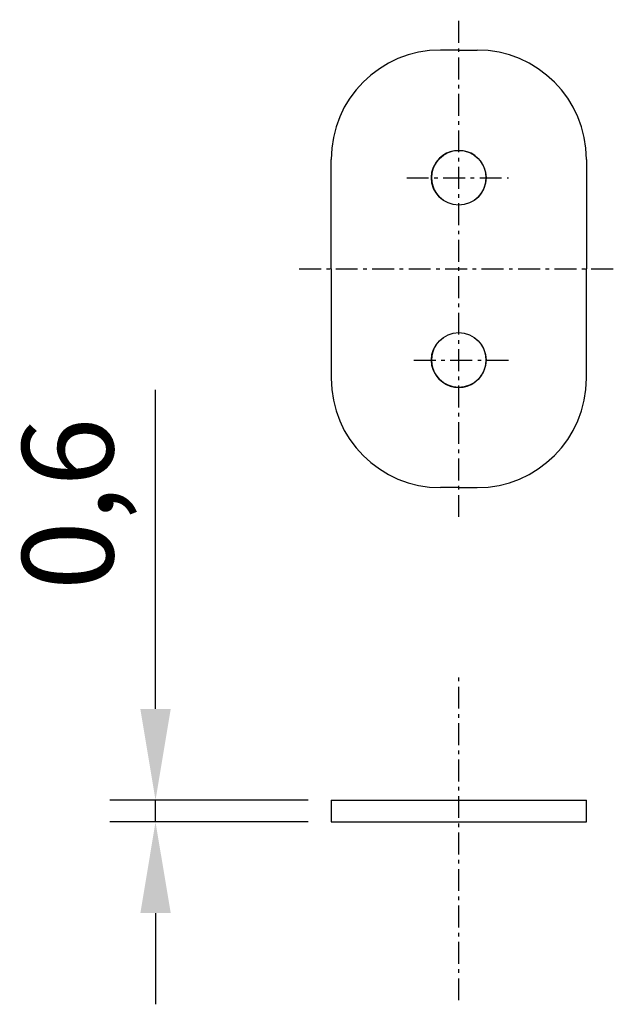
# Model space of a CAD drawing. Units: millimetres. Extents: x -21 to -4.8, y 140.5 to 167.5.
import ezdxf

# ---------------------------------------------------------------- set-up
doc = ezdxf.new("R2010")
doc.units = ezdxf.units.MM
doc.header["$LTSCALE"] = 0.2
doc.linetypes.add('ACAD_ISO10W100', pattern=[18, 12, -3, 0, -3])
doc.dimstyles.new('ISO-25', dxfattribs={"dimtxt": 2.5, "dimasz": 2.5, "dimexe": 1.25, "dimexo": 0.625, "dimtad": 1, "dimtxsty": 'Standard', "dimcen": 2.5, "dimadec": 0, "dimazin": 0, "dimtfac": 1, "dimtmove": 0, "dimatfit": 3, "dimfxl": 0, "dimarcsym": 0})

# ---------------------------------------------------------------- blocks, each defined once
blk = doc.blocks.new('*D1')
at = {"color": 0, "lineweight": -2, "ltscale": 0.25}
for p, q in [((-17.314, 148.583), (-17.314, 157.333)), ((-13.125, 146.083), (-18.564, 146.083)), ((-17.314, 145.483), (-17.314, 146.083)), ((-13.125, 145.483), (-18.564, 145.483)), ((-17.314, 142.983), (-17.314, 140.483))]:
    blk.add_line(p, q, dxfattribs=at)
at = {"color": 0, "lineweight": 15, "ltscale": 0.25}
for points in [[(-17.73, 148.583), (-16.897, 148.583), (-17.314, 146.083)], [(-17.73, 142.983), (-16.897, 142.983), (-17.314, 145.483)]]:
    blk.add_solid(points, dxfattribs=at)
at = {"layer": 'Defpoints', "color": 0, "lineweight": 15, "ltscale": 0.25}
for p in [(-17.314, 146.083), (-12.5, 146.083), (-12.5, 145.483)]:
    blk.add_point(p, dxfattribs=at)
at = {"color": 0, "lineweight": 15, "ltscale": 0.25, "insert": (-19.397, 154.208), "char_height": 2.5, "attachment_point": 5, "rotation": 90}
blk.add_mtext('0,6', dxfattribs=at)

msp = doc.modelspace()

# ---------------------------------------------------------------- linework, layer by layer
at = {"color": 1, "linetype": 'ACAD_ISO10W100', "lineweight": 25, "ltscale": 0.25}
for p, q in [((-9, 153.849), (-9, 167.485)), ((-10.426, 163.152), (-7.634, 163.152)), ((-13.373, 160.652), (-5.137, 160.652)), ((-5.137, 160.652), (-4.764, 160.652)), ((-10.232, 158.152), (-7.634, 158.152)), ((-9, 140.593), (-9, 149.533))]:
    msp.add_line(p, q, dxfattribs=at)
at = {"color": 7, "lineweight": 30, "ltscale": 0.25}
for p, q in [((-9, 166.652), (-9.5, 166.652)), ((-9, 166.652), (-8.5, 166.652)), ((-12.5, 160.652), (-12.5, 163.652)), ((-5.5, 163.652), (-5.5, 160.652)), ((-12.5, 160.652), (-12.5, 157.652)), ((-5.5, 157.652), (-5.5, 160.652)), ((-9, 154.652), (-9.5, 154.652)), ((-9, 154.652), (-8.5, 154.652)), ((-12.5, 146.083), (-12.5, 145.483)), ((-12.5, 146.083), (-5.5, 146.083)), ((-5.5, 145.483), (-5.5, 146.083)), ((-12.5, 145.483), (-5.5, 145.483))]:
    msp.add_line(p, q, dxfattribs=at)
for centre in [(-9, 163.152), (-9, 158.152)]:
    msp.add_circle(centre, 0.75, dxfattribs=at)
for centre, radius, start, end in [((-9.5, 163.652), 3, 90, 180), ((-8.5, 163.652), 3, 0, 90), ((-9, 163.152), 0.75, 306.8699, 233.1301), ((-9, 158.152), 0.75, 126.8699, 53.1301), ((-9.5, 157.652), 3, 180, 270), ((-8.5, 157.652), 3, 270, 0)]:
    msp.add_arc(centre, radius, start, end, dxfattribs=at)

# ---------------------------------------------------------------- dimensions: what is measured, and where the dimension line sits
at = {"color": 3, "lineweight": 15, "ltscale": 0.25}
dim = msp.add_linear_dim(base=(-17.314, 146.083), p1=(-12.5, 145.483), p2=(-12.5, 146.083), angle=90, dimstyle='ISO-25', dxfattribs=at)
dim.commit()
dim.dimension.update_dxf_attribs({"geometry": '*D1', "text_midpoint": (-19.397, 154.208)})

doc.saveas('drawing.dxf')
